VERSION 5.7 ;
  NOWIREEXTENSIONATPIN ON ;
  DIVIDERCHAR "/" ;
  BUSBITCHARS "[]" ;
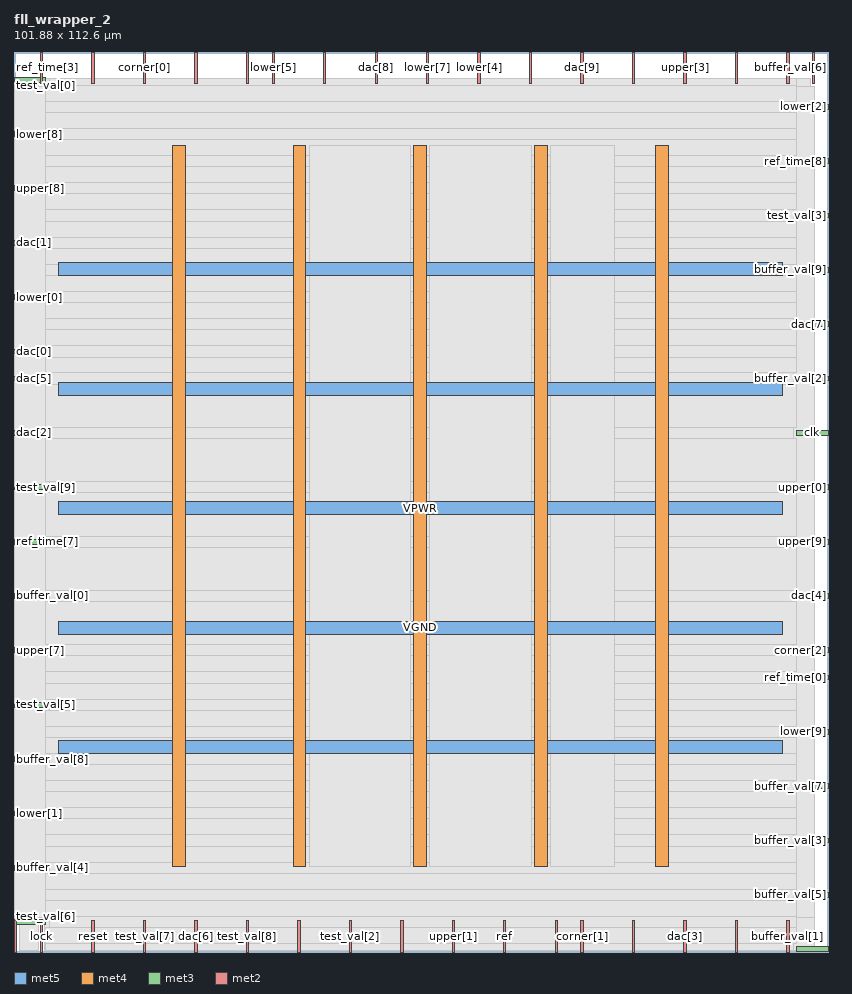
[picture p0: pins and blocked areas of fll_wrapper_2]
MACRO fll_wrapper_2
  CLASS BLOCK ;
  FOREIGN fll_wrapper_2 ;
  ORIGIN 0.000 0.000 ;
  SIZE 101.880 BY 112.600 ;
  PIN VGND
    DIRECTION INPUT ;
    USE GROUND ;
    PORT
      LAYER met5 ;
        RECT 5.520 39.760 96.140 41.360 ;
    END
    PORT
      LAYER met5 ;
        RECT 5.520 69.680 96.140 71.280 ;
    END
    PORT
      LAYER met4 ;
        RECT 34.930 10.640 36.530 100.880 ;
    END
    PORT
      LAYER met4 ;
        RECT 65.135 10.640 66.735 100.880 ;
    END
  END VGND
  PIN VPWR
    DIRECTION INPUT ;
    USE POWER ;
    PORT
      LAYER met5 ;
        RECT 5.520 24.800 96.140 26.400 ;
    END
    PORT
      LAYER met5 ;
        RECT 5.520 54.720 96.140 56.320 ;
    END
    PORT
      LAYER met5 ;
        RECT 5.520 84.640 96.140 86.240 ;
    END
    PORT
      LAYER met4 ;
        RECT 19.820 10.640 21.420 100.880 ;
    END
    PORT
      LAYER met4 ;
        RECT 50.030 10.640 51.630 100.880 ;
    END
    PORT
      LAYER met4 ;
        RECT 80.235 10.640 81.835 100.880 ;
    END
  END VPWR
  PIN buffer_val[0]
    DIRECTION OUTPUT TRISTATE ;
    USE SIGNAL ;
    PORT
      LAYER met3 ;
        RECT 0.000 44.240 4.000 44.840 ;
    END
  END buffer_val[0]
  PIN buffer_val[1]
    DIRECTION OUTPUT TRISTATE ;
    USE SIGNAL ;
    PORT
      LAYER met2 ;
        RECT 96.690 0.000 96.970 4.000 ;
    END
  END buffer_val[1]
  PIN buffer_val[2]
    DIRECTION OUTPUT TRISTATE ;
    USE SIGNAL ;
    PORT
      LAYER met3 ;
        RECT 97.880 71.440 101.880 72.040 ;
    END
  END buffer_val[2]
  PIN buffer_val[3]
    DIRECTION OUTPUT TRISTATE ;
    USE SIGNAL ;
    PORT
      LAYER met3 ;
        RECT 97.880 13.640 101.880 14.240 ;
    END
  END buffer_val[3]
  PIN buffer_val[4]
    DIRECTION OUTPUT TRISTATE ;
    USE SIGNAL ;
    PORT
      LAYER met3 ;
        RECT 0.000 10.240 4.000 10.840 ;
    END
  END buffer_val[4]
  PIN buffer_val[5]
    DIRECTION OUTPUT TRISTATE ;
    USE SIGNAL ;
    PORT
      LAYER met3 ;
        RECT 97.880 6.840 101.880 7.440 ;
    END
  END buffer_val[5]
  PIN buffer_val[6]
    DIRECTION OUTPUT TRISTATE ;
    USE SIGNAL ;
    PORT
      LAYER met2 ;
        RECT 99.910 108.600 100.190 112.600 ;
    END
  END buffer_val[6]
  PIN buffer_val[7]
    DIRECTION OUTPUT TRISTATE ;
    USE SIGNAL ;
    PORT
      LAYER met3 ;
        RECT 97.880 20.440 101.880 21.040 ;
    END
  END buffer_val[7]
  PIN buffer_val[8]
    DIRECTION OUTPUT TRISTATE ;
    USE SIGNAL ;
    PORT
      LAYER met3 ;
        RECT 0.000 23.840 4.000 24.440 ;
    END
  END buffer_val[8]
  PIN buffer_val[9]
    DIRECTION OUTPUT TRISTATE ;
    USE SIGNAL ;
    PORT
      LAYER met3 ;
        RECT 97.880 85.040 101.880 85.640 ;
    END
  END buffer_val[9]
  PIN clk
    DIRECTION INPUT ;
    USE SIGNAL ;
    PORT
      LAYER met3 ;
        RECT 97.880 64.640 101.880 65.240 ;
    END
  END clk
  PIN corner[0]
    DIRECTION OUTPUT TRISTATE ;
    USE SIGNAL ;
    PORT
      LAYER met2 ;
        RECT 16.190 108.600 16.470 112.600 ;
    END
  END corner[0]
  PIN corner[1]
    DIRECTION OUTPUT TRISTATE ;
    USE SIGNAL ;
    PORT
      LAYER met2 ;
        RECT 70.930 0.000 71.210 4.000 ;
    END
  END corner[1]
  PIN corner[2]
    DIRECTION OUTPUT TRISTATE ;
    USE SIGNAL ;
    PORT
      LAYER met3 ;
        RECT 97.880 37.440 101.880 38.040 ;
    END
  END corner[2]
  PIN dac[0]
    DIRECTION OUTPUT TRISTATE ;
    USE SIGNAL ;
    PORT
      LAYER met3 ;
        RECT 0.000 74.840 4.000 75.440 ;
    END
  END dac[0]
  PIN dac[1]
    DIRECTION OUTPUT TRISTATE ;
    USE SIGNAL ;
    PORT
      LAYER met3 ;
        RECT 0.000 88.440 4.000 89.040 ;
    END
  END dac[1]
  PIN dac[2]
    DIRECTION OUTPUT TRISTATE ;
    USE SIGNAL ;
    PORT
      LAYER met3 ;
        RECT 0.000 64.640 4.000 65.240 ;
    END
  END dac[2]
  PIN dac[3]
    DIRECTION OUTPUT TRISTATE ;
    USE SIGNAL ;
    PORT
      LAYER met2 ;
        RECT 83.810 0.000 84.090 4.000 ;
    END
  END dac[3]
  PIN dac[4]
    DIRECTION OUTPUT TRISTATE ;
    USE SIGNAL ;
    PORT
      LAYER met3 ;
        RECT 97.880 44.240 101.880 44.840 ;
    END
  END dac[4]
  PIN dac[5]
    DIRECTION OUTPUT TRISTATE ;
    USE SIGNAL ;
    PORT
      LAYER met3 ;
        RECT 0.000 71.440 4.000 72.040 ;
    END
  END dac[5]
  PIN dac[6]
    DIRECTION OUTPUT TRISTATE ;
    USE SIGNAL ;
    PORT
      LAYER met2 ;
        RECT 22.630 0.000 22.910 4.000 ;
    END
  END dac[6]
  PIN dac[7]
    DIRECTION OUTPUT TRISTATE ;
    USE SIGNAL ;
    PORT
      LAYER met3 ;
        RECT 97.880 78.240 101.880 78.840 ;
    END
  END dac[7]
  PIN dac[8]
    DIRECTION OUTPUT TRISTATE ;
    USE SIGNAL ;
    PORT
      LAYER met2 ;
        RECT 45.170 108.600 45.450 112.600 ;
    END
  END dac[8]
  PIN dac[9]
    DIRECTION OUTPUT TRISTATE ;
    USE SIGNAL ;
    PORT
      LAYER met2 ;
        RECT 70.930 108.600 71.210 112.600 ;
    END
  END dac[9]
  PIN lock
    DIRECTION OUTPUT TRISTATE ;
    USE SIGNAL ;
    PORT
      LAYER met2 ;
        RECT 3.310 0.000 3.590 4.000 ;
    END
  END lock
  PIN lower[0]
    DIRECTION INPUT ;
    USE SIGNAL ;
    PORT
      LAYER met3 ;
        RECT 0.000 81.640 4.000 82.240 ;
    END
  END lower[0]
  PIN lower[1]
    DIRECTION INPUT ;
    USE SIGNAL ;
    PORT
      LAYER met3 ;
        RECT 0.000 17.040 4.000 17.640 ;
    END
  END lower[1]
  PIN lower[2]
    DIRECTION INPUT ;
    USE SIGNAL ;
    PORT
      LAYER met3 ;
        RECT 97.880 105.440 101.880 106.040 ;
    END
  END lower[2]
  PIN lower[3]
    DIRECTION INPUT ;
    USE SIGNAL ;
    PORT
      LAYER met2 ;
        RECT 90.250 0.000 90.530 4.000 ;
    END
  END lower[3]
  PIN lower[4]
    DIRECTION INPUT ;
    USE SIGNAL ;
    PORT
      LAYER met2 ;
        RECT 58.050 108.600 58.330 112.600 ;
    END
  END lower[4]
  PIN lower[5]
    DIRECTION INPUT ;
    USE SIGNAL ;
    PORT
      LAYER met2 ;
        RECT 32.290 108.600 32.570 112.600 ;
    END
  END lower[5]
  PIN lower[6]
    DIRECTION INPUT ;
    USE SIGNAL ;
    PORT
      LAYER met2 ;
        RECT 77.370 0.000 77.650 4.000 ;
    END
  END lower[6]
  PIN lower[7]
    DIRECTION INPUT ;
    USE SIGNAL ;
    PORT
      LAYER met2 ;
        RECT 51.610 108.600 51.890 112.600 ;
    END
  END lower[7]
  PIN lower[8]
    DIRECTION INPUT ;
    USE SIGNAL ;
    PORT
      LAYER met3 ;
        RECT 0.000 102.040 4.000 102.640 ;
    END
  END lower[8]
  PIN lower[9]
    DIRECTION INPUT ;
    USE SIGNAL ;
    PORT
      LAYER met3 ;
        RECT 97.880 27.240 101.880 27.840 ;
    END
  END lower[9]
  PIN ref
    DIRECTION INPUT ;
    USE SIGNAL ;
    PORT
      LAYER met2 ;
        RECT 61.270 0.000 61.550 4.000 ;
    END
  END ref
  PIN ref_time[0]
    DIRECTION INPUT ;
    USE SIGNAL ;
    PORT
      LAYER met3 ;
        RECT 97.880 34.040 101.880 34.640 ;
    END
  END ref_time[0]
  PIN ref_time[1]
    DIRECTION INPUT ;
    USE SIGNAL ;
    PORT
      LAYER met2 ;
        RECT 35.510 0.000 35.790 4.000 ;
    END
  END ref_time[1]
  PIN ref_time[2]
    DIRECTION INPUT ;
    USE SIGNAL ;
    PORT
      LAYER met2 ;
        RECT 77.370 108.600 77.650 112.600 ;
    END
  END ref_time[2]
  PIN ref_time[3]
    DIRECTION INPUT ;
    USE SIGNAL ;
    PORT
      LAYER met2 ;
        RECT 3.310 108.600 3.590 112.600 ;
    END
  END ref_time[3]
  PIN ref_time[4]
    DIRECTION INPUT ;
    USE SIGNAL ;
    PORT
      LAYER met2 ;
        RECT 22.630 108.600 22.910 112.600 ;
    END
  END ref_time[4]
  PIN ref_time[5]
    DIRECTION INPUT ;
    USE SIGNAL ;
    PORT
      LAYER met2 ;
        RECT 48.390 0.000 48.670 4.000 ;
    END
  END ref_time[5]
  PIN ref_time[6]
    DIRECTION INPUT ;
    USE SIGNAL ;
    PORT
      LAYER met2 ;
        RECT 64.490 108.600 64.770 112.600 ;
    END
  END ref_time[6]
  PIN ref_time[7]
    DIRECTION INPUT ;
    USE SIGNAL ;
    PORT
      LAYER met3 ;
        RECT 0.000 51.040 4.000 51.640 ;
    END
  END ref_time[7]
  PIN ref_time[8]
    DIRECTION INPUT ;
    USE SIGNAL ;
    PORT
      LAYER met3 ;
        RECT 97.880 98.640 101.880 99.240 ;
    END
  END ref_time[8]
  PIN ref_time[9]
    DIRECTION INPUT ;
    USE SIGNAL ;
    PORT
      LAYER met2 ;
        RECT 38.730 108.600 39.010 112.600 ;
    END
  END ref_time[9]
  PIN reset
    DIRECTION INPUT ;
    USE SIGNAL ;
    PORT
      LAYER met2 ;
        RECT 9.750 0.000 10.030 4.000 ;
    END
  END reset
  PIN test
    DIRECTION INPUT ;
    USE SIGNAL ;
    PORT
      LAYER met2 ;
        RECT 0.090 0.000 0.370 4.000 ;
    END
  END test
  PIN test_val[0]
    DIRECTION INPUT ;
    USE SIGNAL ;
    PORT
      LAYER met3 ;
        RECT 0.000 108.840 4.000 109.440 ;
    END
  END test_val[0]
  PIN test_val[1]
    DIRECTION INPUT ;
    USE SIGNAL ;
    PORT
      LAYER met2 ;
        RECT 96.690 108.600 96.970 112.600 ;
    END
  END test_val[1]
  PIN test_val[2]
    DIRECTION INPUT ;
    USE SIGNAL ;
    PORT
      LAYER met2 ;
        RECT 41.950 0.000 42.230 4.000 ;
    END
  END test_val[2]
  PIN test_val[3]
    DIRECTION INPUT ;
    USE SIGNAL ;
    PORT
      LAYER met3 ;
        RECT 97.880 91.840 101.880 92.440 ;
    END
  END test_val[3]
  PIN test_val[4]
    DIRECTION INPUT ;
    USE SIGNAL ;
    PORT
      LAYER met3 ;
        RECT 97.880 0.040 101.880 0.640 ;
    END
  END test_val[4]
  PIN test_val[5]
    DIRECTION INPUT ;
    USE SIGNAL ;
    PORT
      LAYER met3 ;
        RECT 0.000 30.640 4.000 31.240 ;
    END
  END test_val[5]
  PIN test_val[6]
    DIRECTION INPUT ;
    USE SIGNAL ;
    PORT
      LAYER met3 ;
        RECT 0.000 3.440 4.000 4.040 ;
    END
  END test_val[6]
  PIN test_val[7]
    DIRECTION INPUT ;
    USE SIGNAL ;
    PORT
      LAYER met2 ;
        RECT 16.190 0.000 16.470 4.000 ;
    END
  END test_val[7]
  PIN test_val[8]
    DIRECTION INPUT ;
    USE SIGNAL ;
    PORT
      LAYER met2 ;
        RECT 29.070 0.000 29.350 4.000 ;
    END
  END test_val[8]
  PIN test_val[9]
    DIRECTION INPUT ;
    USE SIGNAL ;
    PORT
      LAYER met3 ;
        RECT 0.000 57.840 4.000 58.440 ;
    END
  END test_val[9]
  PIN upper[0]
    DIRECTION INPUT ;
    USE SIGNAL ;
    PORT
      LAYER met3 ;
        RECT 97.880 57.840 101.880 58.440 ;
    END
  END upper[0]
  PIN upper[1]
    DIRECTION INPUT ;
    USE SIGNAL ;
    PORT
      LAYER met2 ;
        RECT 54.830 0.000 55.110 4.000 ;
    END
  END upper[1]
  PIN upper[2]
    DIRECTION INPUT ;
    USE SIGNAL ;
    PORT
      LAYER met2 ;
        RECT 90.250 108.600 90.530 112.600 ;
    END
  END upper[2]
  PIN upper[3]
    DIRECTION INPUT ;
    USE SIGNAL ;
    PORT
      LAYER met2 ;
        RECT 83.810 108.600 84.090 112.600 ;
    END
  END upper[3]
  PIN upper[4]
    DIRECTION INPUT ;
    USE SIGNAL ;
    PORT
      LAYER met2 ;
        RECT 9.750 108.600 10.030 112.600 ;
    END
  END upper[4]
  PIN upper[5]
    DIRECTION INPUT ;
    USE SIGNAL ;
    PORT
      LAYER met2 ;
        RECT 29.070 108.600 29.350 112.600 ;
    END
  END upper[5]
  PIN upper[6]
    DIRECTION INPUT ;
    USE SIGNAL ;
    PORT
      LAYER met2 ;
        RECT 67.710 0.000 67.990 4.000 ;
    END
  END upper[6]
  PIN upper[7]
    DIRECTION INPUT ;
    USE SIGNAL ;
    PORT
      LAYER met3 ;
        RECT 0.000 37.440 4.000 38.040 ;
    END
  END upper[7]
  PIN upper[8]
    DIRECTION INPUT ;
    USE SIGNAL ;
    PORT
      LAYER met3 ;
        RECT 0.000 95.240 4.000 95.840 ;
    END
  END upper[8]
  PIN upper[9]
    DIRECTION INPUT ;
    USE SIGNAL ;
    PORT
      LAYER met3 ;
        RECT 97.880 51.040 101.880 51.640 ;
    END
  END upper[9]
  OBS
      LAYER li1 ;
        RECT 5.520 10.795 96.140 100.725 ;
      LAYER met1 ;
        RECT 0.070 6.160 100.210 102.300 ;
      LAYER met2 ;
        RECT 0.100 108.320 3.030 109.325 ;
        RECT 3.870 108.320 9.470 109.325 ;
        RECT 10.310 108.320 15.910 109.325 ;
        RECT 16.750 108.320 22.350 109.325 ;
        RECT 23.190 108.320 28.790 109.325 ;
        RECT 29.630 108.320 32.010 109.325 ;
        RECT 32.850 108.320 38.450 109.325 ;
        RECT 39.290 108.320 44.890 109.325 ;
        RECT 45.730 108.320 51.330 109.325 ;
        RECT 52.170 108.320 57.770 109.325 ;
        RECT 58.610 108.320 64.210 109.325 ;
        RECT 65.050 108.320 70.650 109.325 ;
        RECT 71.490 108.320 77.090 109.325 ;
        RECT 77.930 108.320 83.530 109.325 ;
        RECT 84.370 108.320 89.970 109.325 ;
        RECT 90.810 108.320 96.410 109.325 ;
        RECT 97.250 108.320 99.630 109.325 ;
        RECT 0.100 4.280 100.180 108.320 ;
        RECT 0.650 0.155 3.030 4.280 ;
        RECT 3.870 0.155 9.470 4.280 ;
        RECT 10.310 0.155 15.910 4.280 ;
        RECT 16.750 0.155 22.350 4.280 ;
        RECT 23.190 0.155 28.790 4.280 ;
        RECT 29.630 0.155 35.230 4.280 ;
        RECT 36.070 0.155 41.670 4.280 ;
        RECT 42.510 0.155 48.110 4.280 ;
        RECT 48.950 0.155 54.550 4.280 ;
        RECT 55.390 0.155 60.990 4.280 ;
        RECT 61.830 0.155 67.430 4.280 ;
        RECT 68.270 0.155 70.650 4.280 ;
        RECT 71.490 0.155 77.090 4.280 ;
        RECT 77.930 0.155 83.530 4.280 ;
        RECT 84.370 0.155 89.970 4.280 ;
        RECT 90.810 0.155 96.410 4.280 ;
        RECT 97.250 0.155 100.180 4.280 ;
      LAYER met3 ;
        RECT 4.400 108.440 97.880 109.305 ;
        RECT 4.000 106.440 97.880 108.440 ;
        RECT 4.000 105.040 97.480 106.440 ;
        RECT 4.000 103.040 97.880 105.040 ;
        RECT 4.400 101.640 97.880 103.040 ;
        RECT 4.000 99.640 97.880 101.640 ;
        RECT 4.000 98.240 97.480 99.640 ;
        RECT 4.000 96.240 97.880 98.240 ;
        RECT 4.400 94.840 97.880 96.240 ;
        RECT 4.000 92.840 97.880 94.840 ;
        RECT 4.000 91.440 97.480 92.840 ;
        RECT 4.000 89.440 97.880 91.440 ;
        RECT 4.400 88.040 97.880 89.440 ;
        RECT 4.000 86.040 97.880 88.040 ;
        RECT 4.000 84.640 97.480 86.040 ;
        RECT 4.000 82.640 97.880 84.640 ;
        RECT 4.400 81.240 97.880 82.640 ;
        RECT 4.000 79.240 97.880 81.240 ;
        RECT 4.000 77.840 97.480 79.240 ;
        RECT 4.000 75.840 97.880 77.840 ;
        RECT 4.400 74.440 97.880 75.840 ;
        RECT 4.000 72.440 97.880 74.440 ;
        RECT 4.400 71.040 97.480 72.440 ;
        RECT 4.000 65.640 97.880 71.040 ;
        RECT 4.400 64.240 97.480 65.640 ;
        RECT 4.000 58.840 97.880 64.240 ;
        RECT 4.400 57.440 97.480 58.840 ;
        RECT 4.000 52.040 97.880 57.440 ;
        RECT 4.400 50.640 97.480 52.040 ;
        RECT 4.000 45.240 97.880 50.640 ;
        RECT 4.400 43.840 97.480 45.240 ;
        RECT 4.000 38.440 97.880 43.840 ;
        RECT 4.400 37.040 97.480 38.440 ;
        RECT 4.000 35.040 97.880 37.040 ;
        RECT 4.000 33.640 97.480 35.040 ;
        RECT 4.000 31.640 97.880 33.640 ;
        RECT 4.400 30.240 97.880 31.640 ;
        RECT 4.000 28.240 97.880 30.240 ;
        RECT 4.000 26.840 97.480 28.240 ;
        RECT 4.000 24.840 97.880 26.840 ;
        RECT 4.400 23.440 97.880 24.840 ;
        RECT 4.000 21.440 97.880 23.440 ;
        RECT 4.000 20.040 97.480 21.440 ;
        RECT 4.000 18.040 97.880 20.040 ;
        RECT 4.400 16.640 97.880 18.040 ;
        RECT 4.000 14.640 97.880 16.640 ;
        RECT 4.000 13.240 97.480 14.640 ;
        RECT 4.000 11.240 97.880 13.240 ;
        RECT 4.400 9.840 97.880 11.240 ;
        RECT 4.000 7.840 97.880 9.840 ;
        RECT 4.000 6.440 97.480 7.840 ;
        RECT 4.000 4.440 97.880 6.440 ;
        RECT 4.400 3.040 97.880 4.440 ;
        RECT 4.000 1.040 97.880 3.040 ;
        RECT 4.000 0.175 97.480 1.040 ;
      LAYER met4 ;
        RECT 36.930 10.640 49.630 100.880 ;
        RECT 52.030 10.640 64.735 100.880 ;
        RECT 67.135 10.640 75.145 100.880 ;
  END
END fll_wrapper_2
END LIBRARY

